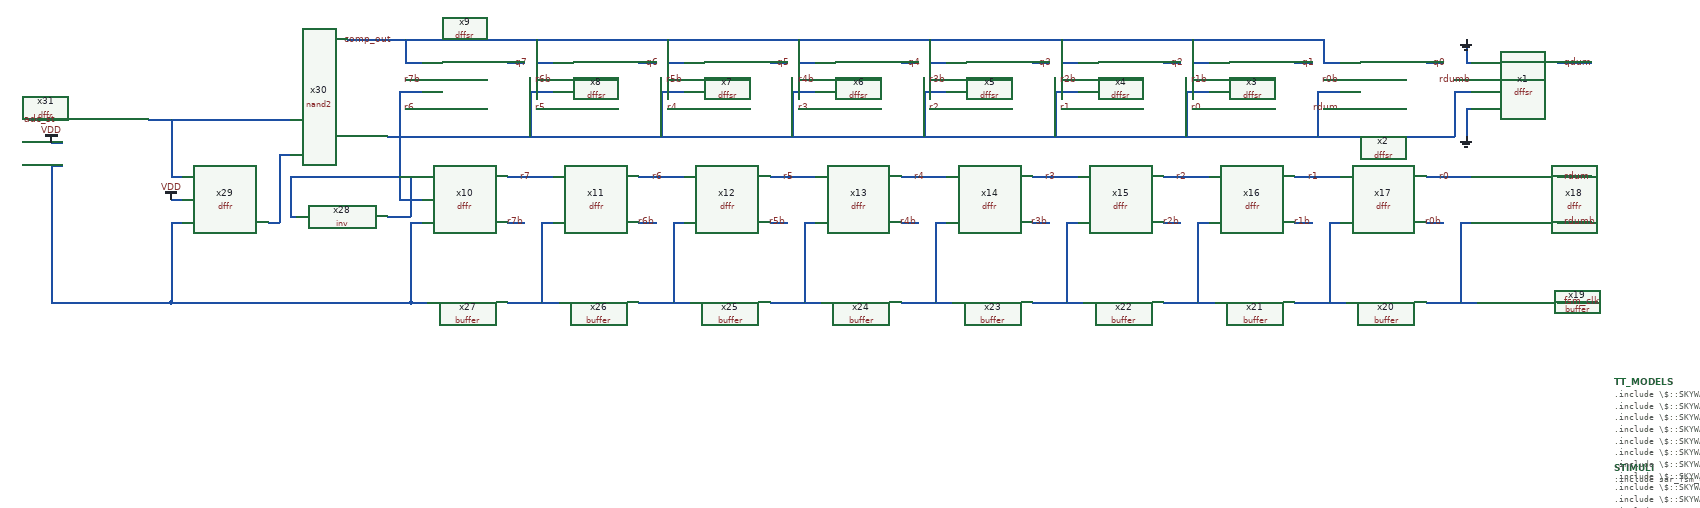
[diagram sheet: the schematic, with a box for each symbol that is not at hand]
v {xschem version=2.9.9 file_version=1.2 }
G {}
K {}
V {}
S {}
E {}
N 30 -920 60 -920 { lab=r6}
N 210 -1000 240 -1000 { lab=q7}
N 30 -1000 60 -1000 { lab=comp_out}
N 260 -920 290 -920 { lab=r5}
N 440 -1000 470 -1000 { lab=q6}
N 260 -1000 290 -1000 { lab=comp_out}
N 490 -920 520 -920 { lab=r4}
N 670 -1000 700 -1000 { lab=q5}
N 490 -1000 520 -1000 { lab=comp_out}
N 720 -920 750 -920 { lab=r3}
N 900 -1000 930 -1000 { lab=q4}
N 720 -1000 750 -1000 { lab=comp_out}
N 950 -920 980 -920 { lab=r2}
N 1130 -1000 1160 -1000 { lab=q3}
N 950 -1000 980 -1000 { lab=comp_out}
N 1180 -920 1210 -920 { lab=r1}
N 1360 -1000 1390 -1000 { lab=q2}
N 1180 -1000 1210 -1000 { lab=comp_out}
N 1410 -920 1440 -920 { lab=r0}
N 1590 -1000 1620 -1000 { lab=q1}
N 1410 -1000 1440 -1000 { lab=comp_out}
N 1640 -920 1670 -920 { lab=rdum}
N 1820 -1000 1850 -1000 { lab=q0}
N 1640 -1000 1670 -1000 { lab=comp_out}
N -70 -1040 1640 -1040 { lab=comp_out}
N 1640 -1040 1640 -1000 { lab=comp_out}
N 1410 -1040 1410 -1000 { lab=comp_out}
N 1180 -1040 1180 -1000 { lab=comp_out}
N 950 -1040 950 -1000 { lab=comp_out}
N 720 -1040 720 -1000 { lab=comp_out}
N 490 -1040 490 -1000 { lab=comp_out}
N 260 -1040 260 -1000 { lab=comp_out}
N 30 -1040 30 -1000 { lab=comp_out}
N 210 -800 290 -800 { lab=r7}
N 440 -800 520 -800 { lab=r6}
N 670 -800 750 -800 { lab=r5}
N 900 -800 980 -800 { lab=r4}
N 1360 -800 1440 -800 { lab=r2}
N 1590 -800 1670 -800 { lab=r1}
N 1820 -800 1900 -800 { lab=r0}
N 1130 -800 1210 -800 { lab=r3}
N 210 -720 240 -720 { lab=r7b}
N 440 -720 470 -720 { lab=r6b}
N 670 -720 700 -720 { lab=r5b}
N 900 -720 930 -720 { lab=r4b}
N 1130 -720 1160 -720 { lab=r3b}
N 1360 -720 1390 -720 { lab=r2b}
N 1590 -720 1620 -720 { lab=r1b}
N 1820 -720 1850 -720 { lab=r0b}
N 30 -970 60 -970 { lab=r7b}
N 260 -970 290 -970 { lab=r6b}
N 490 -970 520 -970 { lab=r5b}
N 720 -970 750 -970 { lab=r4b}
N 950 -970 980 -970 { lab=r3b}
N 1180 -970 1210 -970 { lab=r2b}
N 1410 -970 1440 -970 { lab=r1b}
N 1640 -970 1670 -970 { lab=r0b}
N 1870 -970 1900 -970 { lab=rdumb}
N 210 -580 300 -580 { lab=#net1}
N 440 -580 530 -580 { lab=#net2}
N 670 -580 760 -580 { lab=#net3}
N 900 -580 990 -580 { lab=#net4}
N 1130 -580 1220 -580 { lab=#net5}
N 1360 -580 1450 -580 { lab=#net6}
N 1590 -580 1680 -580 { lab=#net7}
N 1820 -580 1910 -580 { lab=#net8}
N 2050 -580 2120 -580 { lab=fsm_clk}
N 40 -580 70 -580 { lab=#net9}
N 40 -720 40 -580 { lab=#net9}
N 270 -720 290 -720 { lab=#net1}
N 270 -720 270 -580 { lab=#net1}
N 500 -720 520 -720 { lab=#net2}
N 500 -720 500 -580 { lab=#net2}
N 730 -720 750 -720 { lab=#net3}
N 730 -720 730 -580 { lab=#net3}
N 960 -720 980 -720 { lab=#net4}
N 960 -720 960 -580 { lab=#net4}
N 1190 -720 1210 -720 { lab=#net5}
N 1190 -720 1190 -580 { lab=#net5}
N 1420 -720 1440 -720 { lab=#net6}
N 1420 -720 1420 -580 { lab=#net6}
N 1650 -720 1670 -720 { lab=#net7}
N 1650 -720 1650 -580 { lab=#net7}
N 1880 -720 1900 -720 { lab=#net8}
N 1880 -720 1880 -580 { lab=#net8}
N 1870 -950 1870 -870 { lab=#net10}
N 1870 -950 1900 -950 { lab=#net10}
N 1630 -950 1670 -950 { lab=#net10}
N 1630 -950 1630 -870 { lab=#net10}
N 1400 -950 1440 -950 { lab=#net10}
N 1400 -950 1400 -870 { lab=#net10}
N 1170 -950 1210 -950 { lab=#net10}
N 1170 -950 1170 -870 { lab=#net10}
N 940 -950 980 -950 { lab=#net10}
N 940 -950 940 -870 { lab=#net10}
N 710 -950 750 -950 { lab=#net10}
N 710 -950 710 -870 { lab=#net10}
N 480 -950 520 -950 { lab=#net10}
N 480 -950 480 -870 { lab=#net10}
N 250 -950 290 -950 { lab=#net10}
N 250 -950 250 -870 { lab=#net10}
N 20 -950 60 -950 { lab=#net10}
N 20 -950 20 -870 { lab=#net10}
N 40 -720 60 -720 { lab=#net9}
N 2050 -720 2110 -720 { lab=rdumb}
N 2050 -800 2110 -800 { lab=rdum}
N 2050 -1000 2110 -1000 { lab=qdum}
N 20 -870 20 -760 { lab=#net10}
N 20 -760 60 -760 { lab=#net10}
N 1890 -920 1900 -920 { lab=GND}
N 1890 -920 1890 -870 { lab=GND}
N 1890 -1000 1900 -1000 { lab=GND}
N 1890 -1040 1890 -1000 { lab=GND}
N -190 -840 -170 -840 { lab=#net11}
N -380 -800 -360 -800 { lab=#net12}
N -380 -900 -380 -800 { lab=#net12}
N -0 -870 1870 -870 { lab=#net10}
N -190 -840 -190 -720 { lab=#net11}
N -210 -720 -190 -720 { lab=#net11}
N -380 -580 40 -580 { lab=#net9}
N -380 -720 -380 -580 { lab=#net9}
N -380 -720 -360 -720 { lab=#net9}
N -0 -730 40 -730 { lab=#net13}
N 40 -800 40 -730 { lab=#net13}
N 40 -800 60 -800 { lab=#net13}
N -170 -730 -160 -730 { lab=#net10}
N -170 -800 -170 -730 { lab=#net10}
N -170 -800 20 -800 { lab=#net10}
N -630 -900 -570 -900 { lab=adc_st}
N -420 -900 -170 -900 { lab=#net12}
N -590 -820 -570 -820 { lab=#net9}
N -590 -820 -590 -580 { lab=#net9}
N -590 -580 -380 -580 { lab=#net9}
N -590 -860 -570 -860 { lab=VDD}
N -380 -760 -360 -760 { lab=VDD}
C {devices/title.sym} 160 -30 0 0 {name=l1 author="Nikhil Poole"}
C {devices/code.sym} 2150 -290 0 0 {name=STIMULI 
only_toplevel=true
place=end
value=".include sar_fsm_commands.spice"}
C {devices/code.sym} 2150 -440 0 0 {name=TT_MODELS
only_toplevel=true
format="tcleval( @value )"
value="
.include \\\\$::SKYWATER_MODELS\\\\/cells/nfet_01v8/sky130_fd_pr__nfet_01v8__tt.corner.spice
.include \\\\$::SKYWATER_MODELS\\\\/cells/nfet_01v8_lvt/sky130_fd_pr__nfet_01v8_lvt__tt.corner.spice
.include \\\\$::SKYWATER_MODELS\\\\/cells/pfet_01v8/sky130_fd_pr__pfet_01v8__tt.corner.spice
.include \\\\$::SKYWATER_MODELS\\\\/cells/nfet_03v3_nvt/sky130_fd_pr__nfet_03v3_nvt__tt.corner.spice
.include \\\\$::SKYWATER_MODELS\\\\/cells/nfet_05v0_nvt/sky130_fd_pr__nfet_05v0_nvt__tt.corner.spice
.include \\\\$::SKYWATER_MODELS\\\\/cells/esd_nfet_01v8/sky130_fd_pr__esd_nfet_01v8__tt.corner.spice
.include \\\\$::SKYWATER_MODELS\\\\/cells/pfet_01v8_lvt/sky130_fd_pr__pfet_01v8_lvt__tt.corner.spice
.include \\\\$::SKYWATER_MODELS\\\\/cells/pfet_01v8_hvt/sky130_fd_pr__pfet_01v8_hvt__tt.corner.spice
.include \\\\$::SKYWATER_MODELS\\\\/cells/esd_pfet_g5v0d10v5/sky130_fd_pr__esd_pfet_g5v0d10v5__tt.corner.spice
.include \\\\$::SKYWATER_MODELS\\\\/cells/pfet_g5v0d10v5/sky130_fd_pr__pfet_g5v0d10v5__tt.corner.spice
.include \\\\$::SKYWATER_MODELS\\\\/cells/pfet_g5v0d16v0/sky130_fd_pr__pfet_g5v0d16v0__tt.corner.spice
.include \\\\$::SKYWATER_MODELS\\\\/cells/nfet_g5v0d10v5/sky130_fd_pr__nfet_g5v0d10v5__tt.corner.spice
.include \\\\$::SKYWATER_MODELS\\\\/cells/nfet_g5v0d16v0/sky130_fd_pr__nfet_g5v0d16v0__tt_discrete.corner.spice
.include \\\\$::SKYWATER_MODELS\\\\/cells/esd_nfet_g5v0d10v5/sky130_fd_pr__esd_nfet_g5v0d10v5__tt.corner.spice
.include \\\\$::SKYWATER_MODELS\\\\/models/corners/tt/nonfet.spice
* Standard cells
.include \\\\$::SKYWATER_STDCELLS\\\\/cells/inv/sky130_fd_sc_hd__inv_4.spice
* Mismatch parameters
.include \\\\$::SKYWATER_MODELS\\\\/cells/nfet_01v8/sky130_fd_pr__nfet_01v8__mismatch.corner.spice
.include \\\\$::SKYWATER_MODELS\\\\/cells/pfet_01v8/sky130_fd_pr__pfet_01v8__mismatch.corner.spice
.include \\\\$::SKYWATER_MODELS\\\\/cells/nfet_01v8_lvt/sky130_fd_pr__nfet_01v8_lvt__mismatch.corner.spice
.include \\\\$::SKYWATER_MODELS\\\\/cells/pfet_01v8_lvt/sky130_fd_pr__pfet_01v8_lvt__mismatch.corner.spice
.include \\\\$::SKYWATER_MODELS\\\\/cells/pfet_01v8_hvt/sky130_fd_pr__pfet_01v8_hvt__mismatch.corner.spice
.include \\\\$::SKYWATER_MODELS\\\\/cells/nfet_g5v0d10v5/sky130_fd_pr__nfet_g5v0d10v5__mismatch.corner.spice
.include \\\\$::SKYWATER_MODELS\\\\/cells/pfet_g5v0d10v5/sky130_fd_pr__pfet_g5v0d10v5__mismatch.corner.spice
.include \\\\$::SKYWATER_MODELS\\\\/cells/nfet_05v0_nvt/sky130_fd_pr__nfet_05v0_nvt__mismatch.corner.spice
.include \\\\$::SKYWATER_MODELS\\\\/cells/nfet_03v3_nvt/sky130_fd_pr__nfet_03v3_nvt__mismatch.corner.spice
* Resistor\\\\$::SKYWATER_MODELS\\\\/Capacitor
.include \\\\$::SKYWATER_MODELS\\\\/models/r+c/res_typical__cap_typical.spice
.include \\\\$::SKYWATER_MODELS\\\\/models/r+c/res_typical__cap_typical__lin.spice
* Special cells
.include \\\\$::SKYWATER_MODELS\\\\/models/corners/tt/specialized_cells.spice
* All models
.include \\\\$::SKYWATER_MODELS\\\\/models/all.spice
* Corner
.include \\\\$::SKYWATER_MODELS\\\\/models/corners/tt/rf.spice
"}
C {devices/noconn.sym} 210 -920 0 1 {name=l2}
C {devices/lab_wire.sym} 10 -1040 0 0 {name=l3 sig_type=std_logic lab=comp_out}
C {devices/lab_wire.sym} 50 -920 0 0 {name=l4 sig_type=std_logic lab=r6}
C {devices/lab_wire.sym} 220 -1000 0 1 {name=l5 sig_type=std_logic lab=q7}
C {devices/noconn.sym} 440 -920 0 1 {name=l6}
C {devices/lab_wire.sym} 280 -920 0 0 {name=l7 sig_type=std_logic lab=r5}
C {devices/lab_wire.sym} 450 -1000 0 1 {name=l8 sig_type=std_logic lab=q6}
C {devices/noconn.sym} 670 -920 0 1 {name=l9}
C {devices/lab_wire.sym} 510 -920 0 0 {name=l10 sig_type=std_logic lab=r4}
C {devices/lab_wire.sym} 680 -1000 0 1 {name=l11 sig_type=std_logic lab=q5}
C {devices/noconn.sym} 900 -920 0 1 {name=l12}
C {devices/lab_wire.sym} 740 -920 0 0 {name=l13 sig_type=std_logic lab=r3}
C {devices/lab_wire.sym} 910 -1000 0 1 {name=l14 sig_type=std_logic lab=q4}
C {devices/noconn.sym} 1130 -920 0 1 {name=l15}
C {devices/lab_wire.sym} 970 -920 0 0 {name=l16 sig_type=std_logic lab=r2}
C {devices/lab_wire.sym} 1140 -1000 0 1 {name=l17 sig_type=std_logic lab=q3}
C {devices/noconn.sym} 1360 -920 0 1 {name=l18}
C {devices/lab_wire.sym} 1200 -920 0 0 {name=l19 sig_type=std_logic lab=r1}
C {devices/lab_wire.sym} 1370 -1000 0 1 {name=l20 sig_type=std_logic lab=q2}
C {devices/noconn.sym} 1590 -920 0 1 {name=l21}
C {devices/lab_wire.sym} 1430 -920 0 0 {name=l22 sig_type=std_logic lab=r0}
C {devices/lab_wire.sym} 1600 -1000 0 1 {name=l23 sig_type=std_logic lab=q1}
C {devices/noconn.sym} 1820 -920 0 1 {name=l24}
C {devices/lab_wire.sym} 1670 -920 0 0 {name=l25 sig_type=std_logic lab=rdum}
C {devices/lab_wire.sym} 1830 -1000 0 1 {name=l26 sig_type=std_logic lab=q0}
C {devices/noconn.sym} 2050 -920 0 1 {name=l27}
C {devices/lab_wire.sym} 2060 -1000 0 1 {name=l29 sig_type=std_logic lab=qdum}
C {/home/users/nhpoole/ee272b/ee272b_mixed_signal_mmwave_accelerator/designs/dffr.sym} 130 -760 0 0 {name=x10 M=1}
C {/home/users/nhpoole/ee272b/ee272b_mixed_signal_mmwave_accelerator/designs/dffr.sym} 360 -760 0 0 {name=x11 M=1}
C {/home/users/nhpoole/ee272b/ee272b_mixed_signal_mmwave_accelerator/designs/dffr.sym} 590 -760 0 0 {name=x12 M=1}
C {/home/users/nhpoole/ee272b/ee272b_mixed_signal_mmwave_accelerator/designs/dffr.sym} 820 -760 0 0 {name=x13 M=1}
C {/home/users/nhpoole/ee272b/ee272b_mixed_signal_mmwave_accelerator/designs/dffr.sym} 1050 -760 0 0 {name=x14 M=1}
C {/home/users/nhpoole/ee272b/ee272b_mixed_signal_mmwave_accelerator/designs/dffr.sym} 1280 -760 0 0 {name=x15 M=1}
C {/home/users/nhpoole/ee272b/ee272b_mixed_signal_mmwave_accelerator/designs/dffr.sym} 1510 -760 0 0 {name=x16 M=1}
C {/home/users/nhpoole/ee272b/ee272b_mixed_signal_mmwave_accelerator/designs/dffr.sym} 1740 -760 0 0 {name=x17 M=1}
C {devices/lab_wire.sym} 230 -800 0 1 {name=l28 sig_type=std_logic lab=r7}
C {devices/lab_wire.sym} 460 -800 0 1 {name=l30 sig_type=std_logic lab=r6}
C {devices/lab_wire.sym} 690 -800 0 1 {name=l31 sig_type=std_logic lab=r5}
C {devices/lab_wire.sym} 920 -800 0 1 {name=l33 sig_type=std_logic lab=r4}
C {devices/lab_wire.sym} 1380 -800 0 1 {name=l34 sig_type=std_logic lab=r2}
C {devices/lab_wire.sym} 1610 -800 0 1 {name=l35 sig_type=std_logic lab=r1}
C {devices/lab_wire.sym} 1840 -800 0 1 {name=l36 sig_type=std_logic lab=r0}
C {devices/lab_wire.sym} 1150 -800 0 1 {name=l32 sig_type=std_logic lab=r3}
C {/home/users/nhpoole/ee272b/ee272b_mixed_signal_mmwave_accelerator/designs/dffr.sym} 1970 -760 0 0 {name=x18 M=1}
C {devices/lab_wire.sym} 2060 -800 0 1 {name=l37 sig_type=std_logic lab=rdum}
C {/home/users/nhpoole/ee272b/ee272b_mixed_signal_mmwave_accelerator/designs/dffsr.sym} 1970 -960 0 0 {name=x1 M=1}
C {/home/users/nhpoole/ee272b/ee272b_mixed_signal_mmwave_accelerator/designs/dffsr.sym} 1740 -960 0 0 {name=x2 M=1}
C {/home/users/nhpoole/ee272b/ee272b_mixed_signal_mmwave_accelerator/designs/dffsr.sym} 1510 -960 0 0 {name=x3 M=1}
C {/home/users/nhpoole/ee272b/ee272b_mixed_signal_mmwave_accelerator/designs/dffsr.sym} 1280 -960 0 0 {name=x4 M=1}
C {/home/users/nhpoole/ee272b/ee272b_mixed_signal_mmwave_accelerator/designs/dffsr.sym} 1050 -960 0 0 {name=x5 M=1}
C {/home/users/nhpoole/ee272b/ee272b_mixed_signal_mmwave_accelerator/designs/dffsr.sym} 820 -960 0 0 {name=x6 M=1}
C {/home/users/nhpoole/ee272b/ee272b_mixed_signal_mmwave_accelerator/designs/dffsr.sym} 590 -960 0 0 {name=x7 M=1}
C {/home/users/nhpoole/ee272b/ee272b_mixed_signal_mmwave_accelerator/designs/dffsr.sym} 360 -960 0 0 {name=x8 M=1}
C {/home/users/nhpoole/ee272b/ee272b_mixed_signal_mmwave_accelerator/designs/dffsr.sym} 130 -960 0 0 {name=x9 M=1}
C {devices/lab_wire.sym} 240 -720 0 0 {name=l39 sig_type=std_logic lab=r7b}
C {devices/lab_wire.sym} 470 -720 0 0 {name=l40 sig_type=std_logic lab=r6b}
C {devices/lab_wire.sym} 700 -720 0 0 {name=l41 sig_type=std_logic lab=r5b}
C {devices/lab_wire.sym} 930 -720 0 0 {name=l42 sig_type=std_logic lab=r4b}
C {devices/lab_wire.sym} 1160 -720 0 0 {name=l43 sig_type=std_logic lab=r3b}
C {devices/lab_wire.sym} 1390 -720 0 0 {name=l44 sig_type=std_logic lab=r2b}
C {devices/lab_wire.sym} 1620 -720 0 0 {name=l45 sig_type=std_logic lab=r1b}
C {devices/lab_wire.sym} 1850 -720 0 0 {name=l46 sig_type=std_logic lab=r0b}
C {devices/lab_wire.sym} 2060 -720 0 1 {name=l47 sig_type=std_logic lab=rdumb}
C {devices/lab_wire.sym} 60 -970 0 0 {name=l48 sig_type=std_logic lab=r7b}
C {devices/lab_wire.sym} 290 -970 0 0 {name=l49 sig_type=std_logic lab=r6b}
C {devices/lab_wire.sym} 520 -970 0 0 {name=l50 sig_type=std_logic lab=r5b}
C {devices/lab_wire.sym} 750 -970 0 0 {name=l51 sig_type=std_logic lab=r4b}
C {devices/lab_wire.sym} 980 -970 0 0 {name=l52 sig_type=std_logic lab=r3b}
C {devices/lab_wire.sym} 1210 -970 0 0 {name=l53 sig_type=std_logic lab=r2b}
C {devices/lab_wire.sym} 1440 -970 0 0 {name=l54 sig_type=std_logic lab=r1b}
C {devices/lab_wire.sym} 1670 -970 0 0 {name=l55 sig_type=std_logic lab=r0b}
C {devices/lab_wire.sym} 1900 -970 0 0 {name=l56 sig_type=std_logic lab=rdumb}
C {/home/users/nhpoole/ee272b/ee272b_mixed_signal_mmwave_accelerator/designs/buffer.sym} 2000 -580 0 1 {name=x19 M=1}
C {/home/users/nhpoole/ee272b/ee272b_mixed_signal_mmwave_accelerator/designs/buffer.sym} 1770 -580 0 1 {name=x20 M=1}
C {/home/users/nhpoole/ee272b/ee272b_mixed_signal_mmwave_accelerator/designs/buffer.sym} 1540 -580 0 1 {name=x21 M=1}
C {/home/users/nhpoole/ee272b/ee272b_mixed_signal_mmwave_accelerator/designs/buffer.sym} 1310 -580 0 1 {name=x22 M=1}
C {/home/users/nhpoole/ee272b/ee272b_mixed_signal_mmwave_accelerator/designs/buffer.sym} 1080 -580 0 1 {name=x23 M=1}
C {/home/users/nhpoole/ee272b/ee272b_mixed_signal_mmwave_accelerator/designs/buffer.sym} 850 -580 0 1 {name=x24 M=1}
C {/home/users/nhpoole/ee272b/ee272b_mixed_signal_mmwave_accelerator/designs/buffer.sym} 620 -580 0 1 {name=x25 M=1}
C {/home/users/nhpoole/ee272b/ee272b_mixed_signal_mmwave_accelerator/designs/buffer.sym} 390 -580 0 1 {name=x26 M=1}
C {/home/users/nhpoole/ee272b/ee272b_mixed_signal_mmwave_accelerator/designs/buffer.sym} 160 -580 0 1 {name=x27 M=1}
C {devices/lab_wire.sym} 2060 -580 0 1 {name=l57 sig_type=std_logic lab=fsm_clk}
C {devices/gnd.sym} 1890 -870 0 0 {name=l38 lab=GND}
C {devices/gnd.sym} 1890 -1040 2 1 {name=l59 lab=GND}
C {/home/users/nhpoole/ee272b/ee272b_mixed_signal_mmwave_accelerator/designs/dffr.sym} -290 -760 0 0 {name=x29 M=1}
C {devices/noconn.sym} -210 -800 0 1 {name=l60}
C {/home/users/nhpoole/ee272b/ee272b_mixed_signal_mmwave_accelerator/designs/nand2.sym} -100 -870 0 0 {name=x30 M=1}
C {/home/users/nhpoole/ee272b/ee272b_mixed_signal_mmwave_accelerator/designs/inv.sym} -110 -730 0 0 {name=x28 M=1}
C {/home/users/nhpoole/ee272b/ee272b_mixed_signal_mmwave_accelerator/designs/dffr.sym} -500 -860 0 0 {name=x31 M=1}
C {devices/lab_wire.sym} -580 -900 0 0 {name=l61 sig_type=std_logic lab=adc_st}
C {devices/noconn.sym} -420 -820 0 1 {name=l58}
C {devices/vdd.sym} -590 -860 0 0 {name=l62 lab=VDD}
C {devices/vdd.sym} -380 -760 0 0 {name=l63 lab=VDD}
